VERSION 5.7 ;
  NOWIREEXTENSIONATPIN ON ;
  DIVIDERCHAR "/" ;
  BUSBITCHARS "[]" ;
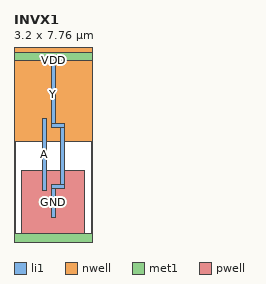
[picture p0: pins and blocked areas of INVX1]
MACRO INVX1
  CLASS CORE ;
  FOREIGN INVX1 ;
  ORIGIN 0.000 0.000 ;
  SIZE 3.200 BY 7.760 ;
  SYMMETRY X Y ;
  SITE unitrh ;
  PIN Y
    DIRECTION OUTPUT ;
    USE SIGNAL ;
    ANTENNADIFFAREA 0.771900 ;
    PORT
      LAYER li1 ;
        RECT 1.520 4.845 1.690 7.200 ;
        RECT 1.520 4.675 2.055 4.845 ;
        RECT 1.885 2.345 2.055 4.675 ;
        RECT 1.515 2.175 2.055 2.345 ;
        RECT 1.515 1.020 1.685 2.175 ;
    END
  END Y
  PIN A
    DIRECTION INPUT ;
    USE SIGNAL ;
    ANTENNAGATEAREA 1.027250 ;
    PORT
      LAYER li1 ;
        RECT 1.145 2.100 1.315 5.045 ;
    END
  END A
  PIN VDD
    DIRECTION INOUT ;
    USE POWER ;
    SHAPE ABUTMENT ;
    PORT
      LAYER nwell ;
        RECT 0.000 4.110 3.200 7.940 ;
      LAYER met1 ;
        RECT 0.000 7.410 3.200 7.760 ;
    END
  END VDD
  PIN GND
    DIRECTION INOUT ;
    USE GROUND ;
    SHAPE ABUTMENT ;
    PORT
      LAYER pwell ;
        RECT 0.320 0.350 2.880 2.900 ;
        RECT 0.000 0.000 3.200 0.350 ;
      LAYER met1 ;
        RECT 0.000 0.000 3.200 0.350 ;
    END
  END GND
  OBS
      LAYER li1 ;
        RECT 0.000 7.410 3.200 7.760 ;
        RECT 0.320 4.290 0.660 7.410 ;
        RECT 1.080 5.365 1.250 7.410 ;
        RECT 1.960 5.365 2.130 7.410 ;
        RECT 2.540 4.290 2.880 7.410 ;
        RECT 0.320 0.350 0.660 2.900 ;
        RECT 1.035 0.800 1.205 1.930 ;
        RECT 2.005 0.800 2.175 1.930 ;
        RECT 1.035 0.630 2.175 0.800 ;
        RECT 1.035 0.350 1.205 0.630 ;
        RECT 1.520 0.350 1.690 0.630 ;
        RECT 2.005 0.350 2.175 0.630 ;
        RECT 2.540 0.350 2.880 2.900 ;
        RECT 0.000 0.000 3.200 0.350 ;
      LAYER mcon ;
        RECT 0.775 7.495 0.945 7.665 ;
        RECT 1.145 7.495 1.315 7.665 ;
        RECT 1.515 7.495 1.685 7.665 ;
        RECT 1.885 7.495 2.055 7.665 ;
        RECT 2.255 7.495 2.425 7.665 ;
        RECT 0.775 0.095 0.945 0.265 ;
        RECT 1.145 0.095 1.315 0.265 ;
        RECT 1.515 0.095 1.685 0.265 ;
        RECT 1.885 0.095 2.055 0.265 ;
        RECT 2.255 0.095 2.425 0.265 ;
  END
END INVX1
END LIBRARY

